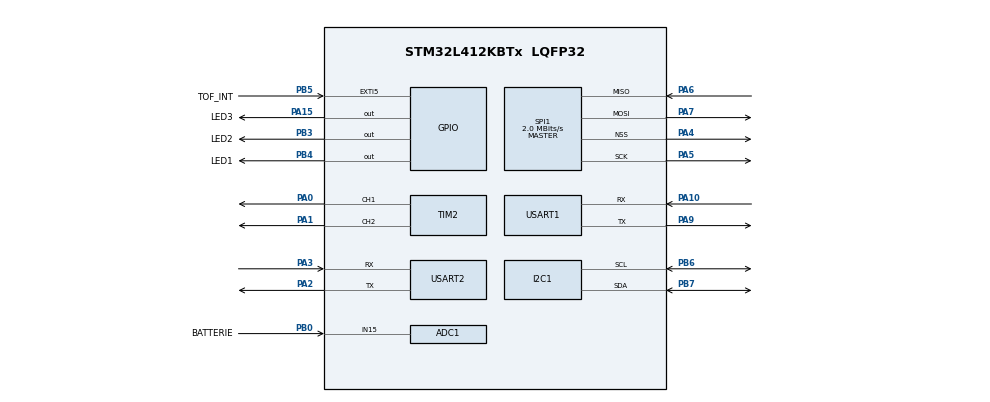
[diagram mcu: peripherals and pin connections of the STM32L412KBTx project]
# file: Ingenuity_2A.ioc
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ADC1.Channel-1\#ChannelRegularConversion=ADC_CHANNEL_15
ADC1.NbrOfConversionFlag=1
ADC1.OffsetNumber-1\#ChannelRegularConversion=ADC_OFFSET_NONE
ADC1.Rank-1\#ChannelRegularConversion=1
ADC1.SamplingTime-1\#ChannelRegularConversion=ADC_SAMPLETIME_2CYCLES_5
ADC1.master=1
Mcu.Family=STM32L4
Mcu.Name=STM32L412KBTx
Mcu.Package=LQFP32
NVIC.PriorityGroup=NVIC_PRIORITYGROUP_4
PA0-CK_IN.Signal=S_TIM2_CH1
PA1.Signal=S_TIM2_CH2
PA10.Mode=Asynchronous
PA10.Signal=USART1_RX
PA13\ (JTMS/SWDIO).Mode=Serial_Wire
PA13\ (JTMS/SWDIO).Signal=SYS_JTMS-SWDIO
PA14\ (JTCK/SWCLK).Mode=Serial_Wire
PA14\ (JTCK/SWCLK).Signal=SYS_JTCK-SWCLK
PA15\ (JTDI).GPIO_Label=LED3
PA15\ (JTDI).Signal=GPIO_Output
PA2.Mode=Asynchronous
PA2.Signal=USART2_TX
PA3.Mode=Asynchronous
PA3.Signal=USART2_RX
PA4.Mode=NSS_Signal_Hard_Output
PA4.Signal=SPI1_NSS
PA5.Mode=Full_Duplex_Master
PA5.Signal=SPI1_SCK
PA6.Mode=Full_Duplex_Master
PA6.Signal=SPI1_MISO
PA7.Mode=Full_Duplex_Master
PA7.Signal=SPI1_MOSI
PA9.Mode=Asynchronous
PA9.Signal=USART1_TX
PB0.GPIO_Label=BATTERIE
PB0.Signal=ADCx_IN15
PB3\ (JTDO/TRACESWO).GPIO_Label=LED2
PB3\ (JTDO/TRACESWO).Signal=GPIO_Output
PB4\ (NJTRST).GPIO_Label=LED1
PB4\ (NJTRST).Signal=GPIO_Output
PB5.GPIO_Label=TOF_INT
PB5.Signal=GPXTI5
PB6.Mode=I2C
PB6.Signal=I2C1_SCL
PB7.Mode=I2C
PB7.Signal=I2C1_SDA
ProjectManager.HeapSize=0x200
ProjectManager.StackSize=0x400
ProjectManager.TargetToolchain=STM32CubeIDE
RCC.ADCFreq_Value=4000000
RCC.HSE_VALUE=8000000
RCC.HSI48_VALUE=48000000
RCC.HSI_VALUE=16000000
RCC.LSE_VALUE=32768
RCC.MSI_VALUE=4000000
RCC.USBFreq_Value=4000000
RCC.VCOOutputFreq_Value=32000000
SH.ADCx_IN15.0=ADC1_IN15,IN15-Single-Ended
SH.S_TIM2_CH1.0=TIM2_CH1,PWM Generation1 CH1
SH.S_TIM2_CH2.0=TIM2_CH2,PWM Generation2 CH2
SPI1.CalculateBaudRate=2.0 MBits/s
SPI1.Direction=SPI_DIRECTION_2LINES
SPI1.Mode=SPI_MODE_MASTER
SPI1.VirtualNSS=VM_NSSHARD
SPI1.VirtualType=VM_MASTER
TIM2.Channel-PWM\ Generation1\ CH1=TIM_CHANNEL_1
TIM2.Channel-PWM\ Generation2\ CH2=TIM_CHANNEL_2
USART1.VirtualMode-Asynchronous=VM_ASYNC
USART2.VirtualMode-Asynchronous=VM_ASYNC
VP_TIM2_VS_ClockSourceINT.Mode=Internal
board=custom

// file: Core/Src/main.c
/* USER CODE BEGIN Header */
/**
  ******************************************************************************
  * @file           : main.c
  * @brief          : Main program body
  ******************************************************************************
  * @attention
  *
  * Copyright (c) 2024 STMicroelectronics.
  * All rights reserved.
  *
  * This software is licensed under terms that can be found in the LICENSE file
  * in the root directory of this software component.
  * If no LICENSE file comes with this software, it is provided AS-IS.
  *
  ******************************************************************************
  */
/* USER CODE END Header */
#include "main.h"

/* USER CODE BEGIN Includes */
#include "motor.h"
#include "decodeInstruction.h"
#include "stdio.h"
#include "stdlib.h"
#include "math.h"

/* USER CODE END Includes */

ADC_HandleTypeDef hadc1;

I2C_HandleTypeDef hi2c1;

SPI_HandleTypeDef hspi1;

TIM_HandleTypeDef htim2;

UART_HandleTypeDef huart1;
UART_HandleTypeDef huart2;

void SystemClock_Config(void);
static void MX_GPIO_Init(void);
static void MX_ADC1_Init(void);
static void MX_I2C1_Init(void);
static void MX_SPI1_Init(void);
static void MX_TIM2_Init(void);
static void MX_USART1_UART_Init(void);
static void MX_USART2_UART_Init(void);

/* USER CODE BEGIN 0 */
int __io_putchar(int ch)
{
  HAL_UART_Transmit(&huart1, (uint8_t *)&ch, 1, HAL_MAX_DELAY);
  return ch;
}

int __io_getchar(void)
{
  uint8_t ch = 0;
  __HAL_UART_CLEAR_OREFLAG(&huart1);
  HAL_UART_Receive(&huart1, (uint8_t *)&ch, 1, HAL_MAX_DELAY);
  HAL_UART_Transmit(&huart1, (uint8_t *)&ch, 1, HAL_MAX_DELAY);
  return ch;
}

char startChar = '@';
char endChar = '#';

uint8_t rx_char; // Variable to store the received character

char instruction[200];
int indexInstruction = 0;

int UARTReceiverState = 0;

volatile int flagUART1 = 0;

void HAL_UART_RxCpltCallback(UART_HandleTypeDef *huart) {
	// Re-enable UART interrupt reception
	HAL_UART_Receive_IT(&huart2, &rx_char, 1);

	instruction[indexInstruction] = rx_char;
	indexInstruction++;

	if (rx_char == '#')
	{
		instruction[indexInstruction] = 0; // 0 character for the printf
		indexInstruction = 0;
		flagUART1 = 1;
	}
}

/* USER CODE END 0 */

int main(void)
{

  /* MCU Configuration--------------------------------------------------------*/

  /* Reset of all peripherals, Initializes the Flash interface and the Systick. */
  HAL_Init();

  /* Configure the system clock */
  SystemClock_Config();

  /* Initialize all configured peripherals */
  MX_GPIO_Init();
  MX_ADC1_Init();
  MX_I2C1_Init();
  MX_SPI1_Init();
  MX_TIM2_Init();
  MX_USART1_UART_Init();
  MX_USART2_UART_Init();
  /* USER CODE BEGIN 2 */

	printf("--------------EXECUTION BEGINS--------------\r\n\n");

	// We define the dictionary of variables that can get modified by receiving a UART signal
	float height = 0.0;
	float LEDState = 0.0;
	char* variableNames[2] = {"height", "LEDState"};
	float* variablePointers[2] = {&height, &LEDState};
	DictOfFloatVariables dictOfVariables = {
		.n = 2,
		.variableNames = variableNames,
		.variables = variablePointers
	};

	// Test to check if applyLabelValue works correctly
	/*
	LabelValue lv_test = {
	    .label = "height",
	    .value = 5.16,
	};
	printf("height = %f\r\n", height);
	applyLabelValue(lv_test, dictOfVariables);
	printf("height = %f\r\n", height);
	 */

	// Test of one motor: initialisation, setting the power to different values, turning off the motor
	/*
	moteur upperMotor;
	upperMotor.htim = &htim2;
	upperMotor.channel = TIM_CHANNEL_1;
	MOTEUR_Init(&upperMotor);

	printf("START OF TEST+++++++++++++++");

	MOTEUR_SetPower(&upperMotor, 30);
	HAL_Delay(5000);
	MOTEUR_TurnOff(&upperMotor);

	HAL_Delay(5000);

	MOTEUR_SetPower(&upperMotor, 50);
	HAL_Delay(5000);
	MOTEUR_TurnOff(&upperMotor);

	printf("END OF TEST++++++++++++++++");
	*/

	// Important, initiate character reception.
	// This line also being in HAL_UART_RxCpltCallback's body ensures continuous reception
	HAL_UART_Receive_IT(&huart1, &rx_char, 1);

  /* USER CODE END 2 */

  /* Infinite loop */
  /* USER CODE BEGIN WHILE */
  while (1)
  {
	  // This is a test to check that instructions can correctly be received
	  // by UART and affect change (modified variables, LED toggled)
	  if (flagUART1 == 1) {
		  printf("instruction = %s\r\n", instruction);

		  flagUART1 = 0;

		  LabelValue lv = checkInstruction(instruction);
		  printLabelValue(lv);

		  printf("height = %f\r\n", height);
		  applyLabelValue(lv, dictOfVariables);
		  printf("height = %f\r\n", height);

		  // This will not be the final use of height, it is just a test
		  if(height >= 1) {
			  HAL_GPIO_WritePin(GPIOA, GPIO_PIN_15, GPIO_PIN_SET);
		  } else {
			  HAL_GPIO_WritePin(GPIOA, GPIO_PIN_15, GPIO_PIN_RESET);
		  }
	  }
    /* USER CODE END WHILE */

  }
}

void SystemClock_Config(void)
{
  RCC_OscInitTypeDef RCC_OscInitStruct = {0};
  RCC_ClkInitTypeDef RCC_ClkInitStruct = {0};

  /** Configure the main internal regulator output voltage
  */
  if (HAL_PWREx_ControlVoltageScaling(PWR_REGULATOR_VOLTAGE_SCALE1) != HAL_OK)
  {
    Error_Handler();
  }

  /** Initializes the RCC Oscillators according to the specified parameters
  * in the RCC_OscInitTypeDef structure.
  */
  RCC_OscInitStruct.OscillatorType = RCC_OSCILLATORTYPE_MSI;
  RCC_OscInitStruct.MSIState = RCC_MSI_ON;
  RCC_OscInitStruct.MSICalibrationValue = 0;
  RCC_OscInitStruct.MSIClockRange = RCC_MSIRANGE_6;
  RCC_OscInitStruct.PLL.PLLState = RCC_PLL_ON;
  RCC_OscInitStruct.PLL.PLLSource = RCC_PLLSOURCE_MSI;
  RCC_OscInitStruct.PLL.PLLM = 1;
  RCC_OscInitStruct.PLL.PLLN = 40;
  RCC_OscInitStruct.PLL.PLLQ = RCC_PLLQ_DIV2;
  RCC_OscInitStruct.PLL.PLLR = RCC_PLLR_DIV2;
  if (HAL_RCC_OscConfig(&RCC_OscInitStruct) != HAL_OK)
  {
    Error_Handler();
  }

  /** Initializes the CPU, AHB and APB buses clocks
  */
  RCC_ClkInitStruct.ClockType = RCC_CLOCKTYPE_HCLK|RCC_CLOCKTYPE_SYSCLK
                              |RCC_CLOCKTYPE_PCLK1|RCC_CLOCKTYPE_PCLK2;
  RCC_ClkInitStruct.SYSCLKSource = RCC_SYSCLKSOURCE_PLLCLK;
  RCC_ClkInitStruct.AHBCLKDivider = RCC_SYSCLK_DIV1;
  RCC_ClkInitStruct.APB1CLKDivider = RCC_HCLK_DIV1;
  RCC_ClkInitStruct.APB2CLKDivider = RCC_HCLK_DIV1;

  if (HAL_RCC_ClockConfig(&RCC_ClkInitStruct, FLASH_LATENCY_4) != HAL_OK)
  {
    Error_Handler();
  }
}

static void MX_ADC1_Init(void)
{

  ADC_MultiModeTypeDef multimode = {0};
  ADC_ChannelConfTypeDef sConfig = {0};

  /** Common config
  */
  hadc1.Instance = ADC1;
  hadc1.Init.ClockPrescaler = ADC_CLOCK_ASYNC_DIV1;
  hadc1.Init.Resolution = ADC_RESOLUTION_12B;
  hadc1.Init.DataAlign = ADC_DATAALIGN_RIGHT;
  hadc1.Init.ScanConvMode = ADC_SCAN_DISABLE;
  hadc1.Init.EOCSelection = ADC_EOC_SINGLE_CONV;
  hadc1.Init.LowPowerAutoWait = DISABLE;
  hadc1.Init.ContinuousConvMode = DISABLE;
  hadc1.Init.NbrOfConversion = 1;
  hadc1.Init.DiscontinuousConvMode = DISABLE;
  hadc1.Init.ExternalTrigConv = ADC_SOFTWARE_START;
  hadc1.Init.ExternalTrigConvEdge = ADC_EXTERNALTRIGCONVEDGE_NONE;
  hadc1.Init.DMAContinuousRequests = DISABLE;
  hadc1.Init.Overrun = ADC_OVR_DATA_PRESERVED;
  hadc1.Init.OversamplingMode = DISABLE;
  if (HAL_ADC_Init(&hadc1) != HAL_OK)
  {
    Error_Handler();
  }

  /** Configure the ADC multi-mode
  */
  multimode.Mode = ADC_MODE_INDEPENDENT;
  if (HAL_ADCEx_MultiModeConfigChannel(&hadc1, &multimode) != HAL_OK)
  {
    Error_Handler();
  }

  /** Configure Regular Channel
  */
  sConfig.Channel = ADC_CHANNEL_15;
  sConfig.Rank = ADC_REGULAR_RANK_1;
  sConfig.SamplingTime = ADC_SAMPLETIME_2CYCLES_5;
  sConfig.SingleDiff = ADC_SINGLE_ENDED;
  sConfig.OffsetNumber = ADC_OFFSET_NONE;
  sConfig.Offset = 0;
  if (HAL_ADC_ConfigChannel(&hadc1, &sConfig) != HAL_OK)
  {
    Error_Handler();
  }

}

static void MX_I2C1_Init(void)
{

  hi2c1.Instance = I2C1;
  hi2c1.Init.Timing = 0x10909CEC;
  hi2c1.Init.OwnAddress1 = 0;
  hi2c1.Init.AddressingMode = I2C_ADDRESSINGMODE_7BIT;
  hi2c1.Init.DualAddressMode = I2C_DUALADDRESS_DISABLE;
  hi2c1.Init.OwnAddress2 = 0;
  hi2c1.Init.OwnAddress2Masks = I2C_OA2_NOMASK;
  hi2c1.Init.GeneralCallMode = I2C_GENERALCALL_DISABLE;
  hi2c1.Init.NoStretchMode = I2C_NOSTRETCH_DISABLE;
  if (HAL_I2C_Init(&hi2c1) != HAL_OK)
  {
    Error_Handler();
  }

  /** Configure Analogue filter
  */
  if (HAL_I2CEx_ConfigAnalogFilter(&hi2c1, I2C_ANALOGFILTER_ENABLE) != HAL_OK)
  {
    Error_Handler();
  }

  /** Configure Digital filter
  */
  if (HAL_I2CEx_ConfigDigitalFilter(&hi2c1, 0) != HAL_OK)
  {
    Error_Handler();
  }

}

static void MX_SPI1_Init(void)
{

  /* SPI1 parameter configuration*/
  hspi1.Instance = SPI1;
  hspi1.Init.Mode = SPI_MODE_MASTER;
  hspi1.Init.Direction = SPI_DIRECTION_2LINES;
  hspi1.Init.DataSize = SPI_DATASIZE_4BIT;
  hspi1.Init.CLKPolarity = SPI_POLARITY_LOW;
  hspi1.Init.CLKPhase = SPI_PHASE_1EDGE;
  hspi1.Init.NSS = SPI_NSS_HARD_OUTPUT;
  hspi1.Init.BaudRatePrescaler = SPI_BAUDRATEPRESCALER_2;
  hspi1.Init.FirstBit = SPI_FIRSTBIT_MSB;
  hspi1.Init.TIMode = SPI_TIMODE_DISABLE;
  hspi1.Init.CRCCalculation = SPI_CRCCALCULATION_DISABLE;
  hspi1.Init.CRCPolynomial = 7;
  hspi1.Init.CRCLength = SPI_CRC_LENGTH_DATASIZE;
  hspi1.Init.NSSPMode = SPI_NSS_PULSE_ENABLE;
  if (HAL_SPI_Init(&hspi1) != HAL_OK)
  {
    Error_Handler();
  }

}

static void MX_TIM2_Init(void)
{

  TIM_ClockConfigTypeDef sClockSourceConfig = {0};
  TIM_MasterConfigTypeDef sMasterConfig = {0};
  TIM_OC_InitTypeDef sConfigOC = {0};

  htim2.Instance = TIM2;
  htim2.Init.Prescaler = 80;
  htim2.Init.CounterMode = TIM_COUNTERMODE_UP;
  htim2.Init.Period = 19999;
  htim2.Init.ClockDivision = TIM_CLOCKDIVISION_DIV1;
  htim2.Init.AutoReloadPreload = TIM_AUTORELOAD_PRELOAD_DISABLE;
  if (HAL_TIM_Base_Init(&htim2) != HAL_OK)
  {
    Error_Handler();
  }
  sClockSourceConfig.ClockSource = TIM_CLOCKSOURCE_INTERNAL;
  if (HAL_TIM_ConfigClockSource(&htim2, &sClockSourceConfig) != HAL_OK)
  {
    Error_Handler();
  }
  if (HAL_TIM_PWM_Init(&htim2) != HAL_OK)
  {
    Error_Handler();
  }
  sMasterConfig.MasterOutputTrigger = TIM_TRGO_RESET;
  sMasterConfig.MasterSlaveMode = TIM_MASTERSLAVEMODE_DISABLE;
  if (HAL_TIMEx_MasterConfigSynchronization(&htim2, &sMasterConfig) != HAL_OK)
  {
    Error_Handler();
  }
  sConfigOC.OCMode = TIM_OCMODE_PWM1;
  sConfigOC.Pulse = 0;
  sConfigOC.OCPolarity = TIM_OCPOLARITY_HIGH;
  sConfigOC.OCFastMode = TIM_OCFAST_DISABLE;
  if (HAL_TIM_PWM_ConfigChannel(&htim2, &sConfigOC, TIM_CHANNEL_1) != HAL_OK)
  {
    Error_Handler();
  }
  if (HAL_TIM_PWM_ConfigChannel(&htim2, &sConfigOC, TIM_CHANNEL_2) != HAL_OK)
  {
    Error_Handler();
  }
  HAL_TIM_MspPostInit(&htim2);

}

static void MX_USART1_UART_Init(void)
{

  huart1.Instance = USART1;
  huart1.Init.BaudRate = 115200;
  huart1.Init.WordLength = UART_WORDLENGTH_8B;
  huart1.Init.StopBits = UART_STOPBITS_1;
  huart1.Init.Parity = UART_PARITY_NONE;
  huart1.Init.Mode = UART_MODE_TX_RX;
  huart1.Init.HwFlowCtl = UART_HWCONTROL_NONE;
  huart1.Init.OverSampling = UART_OVERSAMPLING_16;
  huart1.Init.OneBitSampling = UART_ONE_BIT_SAMPLE_DISABLE;
  huart1.AdvancedInit.AdvFeatureInit = UART_ADVFEATURE_NO_INIT;
  if (HAL_UART_Init(&huart1) != HAL_OK)
  {
    Error_Handler();
  }

}

static void MX_USART2_UART_Init(void)
{

  huart2.Instance = USART2;
  huart2.Init.BaudRate = 115200;
  huart2.Init.WordLength = UART_WORDLENGTH_8B;
  huart2.Init.StopBits = UART_STOPBITS_1;
  huart2.Init.Parity = UART_PARITY_NONE;
  huart2.Init.Mode = UART_MODE_TX_RX;
  huart2.Init.HwFlowCtl = UART_HWCONTROL_NONE;
  huart2.Init.OverSampling = UART_OVERSAMPLING_16;
  huart2.Init.OneBitSampling = UART_ONE_BIT_SAMPLE_DISABLE;
  huart2.AdvancedInit.AdvFeatureInit = UART_ADVFEATURE_NO_INIT;
  if (HAL_UART_Init(&huart2) != HAL_OK)
  {
    Error_Handler();
  }

}

static void MX_GPIO_Init(void)
{
  GPIO_InitTypeDef GPIO_InitStruct = {0};

  /* GPIO Ports Clock Enable */
  __HAL_RCC_GPIOA_CLK_ENABLE();
  __HAL_RCC_GPIOB_CLK_ENABLE();

  /*Configure GPIO pin Output Level */
  HAL_GPIO_WritePin(LED3_GPIO_Port, LED3_Pin, GPIO_PIN_RESET);

  /*Configure GPIO pin Output Level */
  HAL_GPIO_WritePin(GPIOB, LED2_Pin|LED1_Pin, GPIO_PIN_RESET);

  /*Configure GPIO pin : LED3_Pin */
  GPIO_InitStruct.Pin = LED3_Pin;
  GPIO_InitStruct.Mode = GPIO_MODE_OUTPUT_PP;
  GPIO_InitStruct.Pull = GPIO_NOPULL;
  GPIO_InitStruct.Speed = GPIO_SPEED_FREQ_LOW;
  HAL_GPIO_Init(LED3_GPIO_Port, &GPIO_InitStruct);

  /*Configure GPIO pins : LED2_Pin LED1_Pin */
  GPIO_InitStruct.Pin = LED2_Pin|LED1_Pin;
  GPIO_InitStruct.Mode = GPIO_MODE_OUTPUT_PP;
  GPIO_InitStruct.Pull = GPIO_NOPULL;
  GPIO_InitStruct.Speed = GPIO_SPEED_FREQ_LOW;
  HAL_GPIO_Init(GPIOB, &GPIO_InitStruct);

  /*Configure GPIO pin : TOF_INT_Pin */
  GPIO_InitStruct.Pin = TOF_INT_Pin;
  GPIO_InitStruct.Mode = GPIO_MODE_IT_RISING;
  GPIO_InitStruct.Pull = GPIO_NOPULL;
  HAL_GPIO_Init(TOF_INT_GPIO_Port, &GPIO_InitStruct);

}

void Error_Handler(void)
{
  __disable_irq();
  while (1)
  {
  }
}
